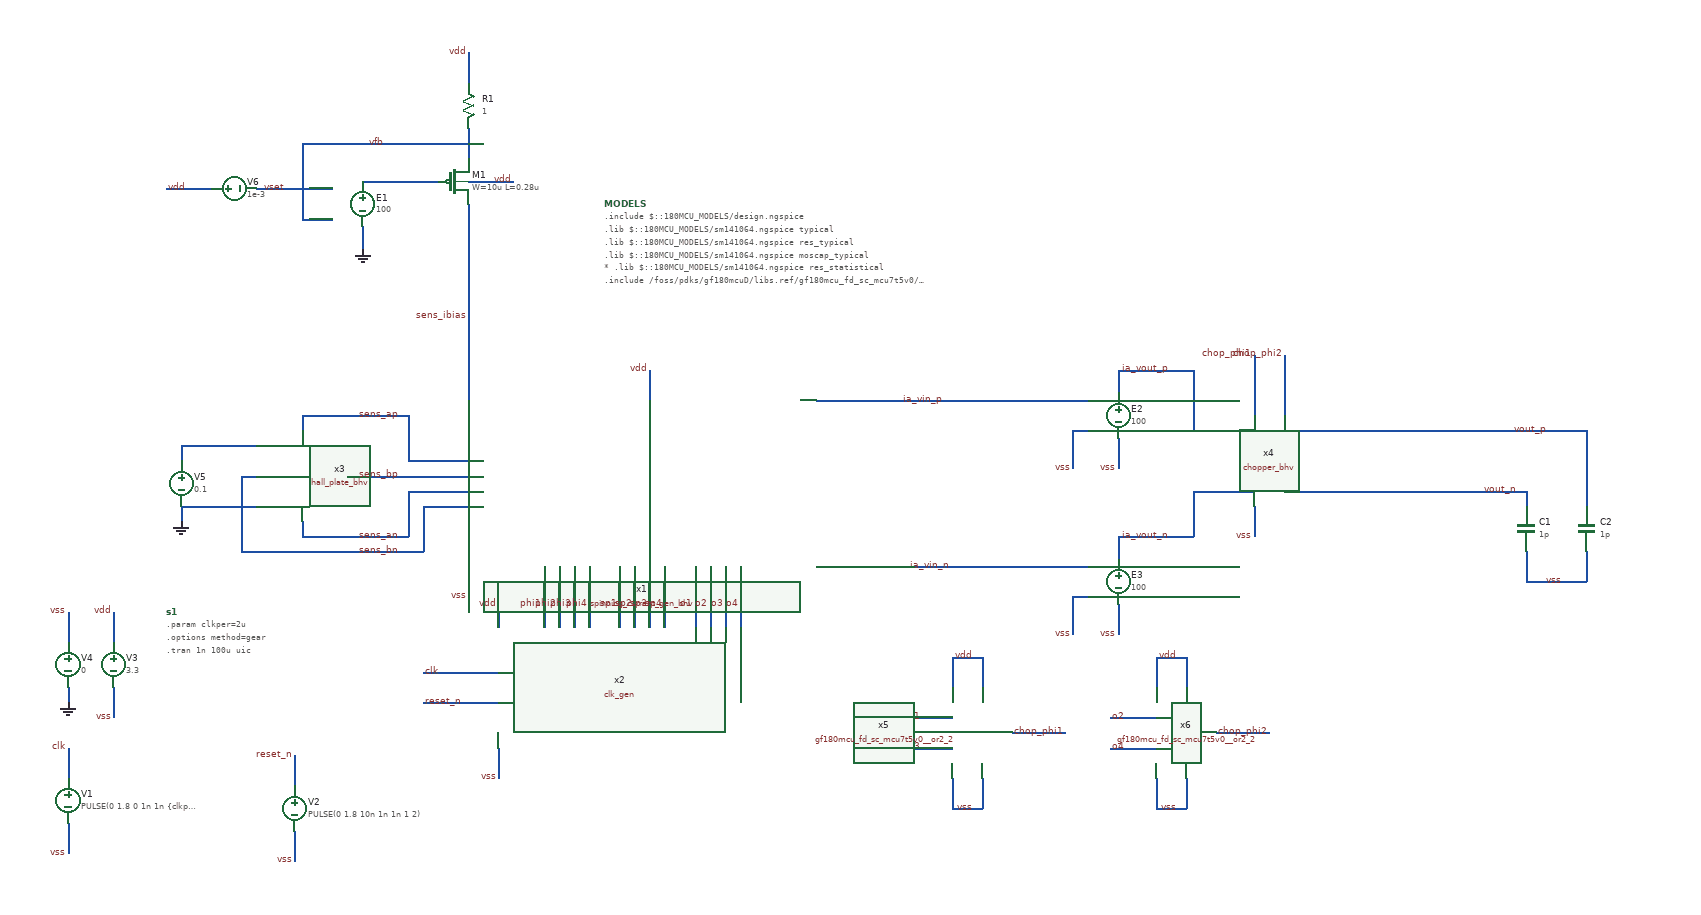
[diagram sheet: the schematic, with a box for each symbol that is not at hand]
v {xschem version=3.4.8RC file_version=1.3}
G {}
K {}
V {}
S {}
F {}
E {}
N 1020 -480 1020 -400 {lab=phi1}
N 1040 -480 1040 -400 {lab=phi2}
N 1060 -480 1060 -400 {lab=phi3}
N 1080 -480 1080 -400 {lab=phi4}
N 1120 -480 1120 -400 {lab=sp1}
N 1140 -480 1140 -400 {lab=sp2}
N 1160 -480 1160 -400 {lab=sp3}
N 1180 -480 1180 -400 {lab=sp4}
N 1220 -480 1220 -400 {lab=o1}
N 1240 -480 1240 -400 {lab=o2}
N 1260 -480 1260 -400 {lab=o3}
N 1280 -480 1280 -400 {lab=o4}
N 700 -680 700 -660 {lab=sens_ap}
N 710 -680 840 -680 {lab=sens_ap}
N 840 -680 840 -620 {lab=sens_ap}
N 840 -620 920 -620 {lab=sens_ap}
N 770 -600 920 -600 {lab=sens_bp}
N 710 -520 840 -520 {lab=sens_an}
N 840 -580 840 -520 {lab=sens_an}
N 840 -580 920 -580 {lab=sens_an}
N 700 -680 710 -680 {lab=sens_ap}
N 700 -520 710 -520 {lab=sens_an}
N 700 -540 700 -520 {lab=sens_an}
N 880 -560 920 -560 {lab=sens_bn}
N 860 -560 860 -500 {lab=sens_bn}
N 620 -600 620 -500 {lab=sens_bn}
N 620 -600 640 -600 {lab=sens_bn}
N 860 -560 880 -560 {lab=sens_bn}
N 620 -500 860 -500 {lab=sens_bn}
N 920 -480 920 -440 {lab=vss}
N 1160 -740 1160 -700 {lab=vdd}
N 920 -820 920 -700 {lab=sens_ibias}
N 1380 -700 1480 -700 {lab=ia_vin_p}
N 1380 -480 1480 -480 {lab=ia_vin_n}
N 960 -420 960 -400 {lab=vdd}
N 960 -430 960 -420 {lab=vdd}
N 960 -240 960 -200 {lab=vss}
N 760 -600 770 -600 {lab=sens_bp}
N 860 -340 960 -340 {lab=clk}
N 860 -300 960 -300 {lab=reset_n}
N 390 -320 390 -300 {lab=0}
N 390 -420 390 -390 {lab=vss}
N 390 -390 390 -380 {lab=vss}
N 450 -320 450 -300 {lab=vss}
N 450 -300 450 -280 {lab=vss}
N 450 -420 450 -380 {lab=vdd}
N 390 -140 390 -120 {lab=vss}
N 390 -120 390 -100 {lab=vss}
N 390 -240 390 -200 {lab=clk}
N 690 -130 690 -110 {lab=vss}
N 690 -110 690 -90 {lab=vss}
N 690 -230 690 -190 {lab=reset_n}
N 550 -640 640 -640 {lab=#net1}
N 540 -560 640 -560 {lab=0}
N 540 -640 550 -640 {lab=#net1}
N 540 -640 540 -620 {lab=#net1}
N 540 -560 540 -540 {lab=0}
N 920 -920 920 -820 {lab=sens_ibias}
N 920 -960 920 -920 {lab=sens_ibias}
N 920 -990 980 -990 {lab=vdd}
N 920 -1060 920 -1020 {lab=vfb}
N 780 -990 880 -990 {lab=#net2}
N 700 -1040 920 -1040 {lab=vfb}
N 640 -980 680 -980 {lab=vset}
N 920 -1160 920 -1120 {lab=vdd}
N 520 -980 580 -980 {lab=vdd}
N 780 -930 780 -900 {lab=0}
N 700 -940 740 -940 {lab=vfb}
N 700 -1040 700 -940 {lab=vfb}
N 680 -980 740 -980 {lab=vset}
N 1780 -650 1780 -610 {lab=vss}
N 1780 -430 1780 -390 {lab=vss}
N 1480 -480 1740 -480 {lab=ia_vin_n}
N 1480 -700 1740 -700 {lab=ia_vin_p}
N 1720 -650 1720 -610 {lab=vss}
N 1720 -430 1720 -390 {lab=vss}
N 1720 -660 1720 -650 {lab=vss}
N 1720 -660 1740 -660 {lab=vss}
N 1720 -440 1720 -430 {lab=vss}
N 1720 -440 1740 -440 {lab=vss}
N 1780 -740 1780 -710 {lab=ia_vout_p}
N 1780 -740 1880 -740 {lab=ia_vout_p}
N 1780 -520 1780 -490 {lab=ia_vout_n}
N 1780 -520 1880 -520 {lab=ia_vout_n}
N 1880 -740 1880 -660 {lab=ia_vout_p}
N 1880 -660 1960 -660 {lab=ia_vout_p}
N 1880 -580 1880 -520 {lab=ia_vout_n}
N 1880 -580 1960 -580 {lab=ia_vout_n}
N 2000 -660 2100 -660 {lab=vout_p}
N 2000 -580 2100 -580 {lab=vout_n}
N 2320 -580 2320 -560 {lab=vout_n}
N 2320 -660 2400 -660 {lab=vout_p}
N 2400 -660 2400 -560 {lab=vout_p}
N 2320 -500 2320 -460 {lab=vss}
N 2320 -460 2400 -460 {lab=vss}
N 2400 -500 2400 -460 {lab=vss}
N 1500 -280 1560 -280 {lab=o1}
N 1500 -240 1560 -240 {lab=o3}
N 1560 -360 1560 -320 {lab=vdd}
N 1600 -360 1600 -320 {lab=vdd}
N 1560 -360 1600 -360 {lab=vdd}
N 1560 -200 1560 -160 {lab=vss}
N 1560 -160 1600 -160 {lab=vss}
N 1600 -200 1600 -160 {lab=vss}
N 1960 -560 1960 -520 {lab=vss}
N 1680 -260 1710 -260 {lab=chop_phi1}
N 1770 -280 1830 -280 {lab=o2}
N 1770 -240 1830 -240 {lab=o4}
N 1830 -360 1830 -320 {lab=vdd}
N 1870 -360 1870 -320 {lab=vdd}
N 1830 -360 1870 -360 {lab=vdd}
N 1830 -200 1830 -160 {lab=vss}
N 1830 -160 1870 -160 {lab=vss}
N 1870 -200 1870 -160 {lab=vss}
N 1950 -260 1980 -260 {lab=chop_phi2}
N 1960 -750 1960 -680 {lab=chop_phi1}
N 2000 -750 2000 -680 {lab=chop_phi2}
N 1960 -760 1960 -750 {lab=chop_phi1}
N 2000 -760 2000 -750 {lab=chop_phi2}
N 1640 -260 1680 -260 {lab=chop_phi1}
N 1910 -260 1950 -260 {lab=chop_phi2}
N 2100 -580 2140 -580 {lab=vout_n}
N 2100 -660 2140 -660 {lab=vout_p}
N 2200 -660 2320 -660 {lab=vout_p}
N 2200 -580 2320 -580 {lab=vout_n}
N 2140 -660 2200 -660 {lab=vout_p}
N 2140 -580 2200 -580 {lab=vout_n}
C {title.sym} 160 -40 0 0 {name=l1 author="alang"}
C {spinning_current_gen_bhv/spinning_current_gen_bhv.sym} 920 -480 0 0 {name=x1}
C {hall_plate_bhv/hall_plate_bhv.sym} 640 -540 0 0 {name=x3}
C {lab_wire.sym} 830 -680 0 0 {name=p17 sig_type=std_logic lab=sens_ap}
C {lab_wire.sym} 830 -600 0 0 {name=p18 sig_type=std_logic lab=sens_bp}
C {lab_wire.sym} 830 -520 0 0 {name=p19 sig_type=std_logic lab=sens_an}
C {lab_wire.sym} 830 -500 0 0 {name=p20 sig_type=std_logic lab=sens_bn}
C {lab_wire.sym} 920 -440 1 0 {name=p21 sig_type=std_logic lab=vss}
C {lab_wire.sym} 1160 -740 1 1 {name=p22 sig_type=std_logic lab=vdd}
C {lab_wire.sym} 960 -430 3 0 {name=p23 sig_type=std_logic lab=vdd}
C {lab_wire.sym} 960 -200 3 1 {name=p24 sig_type=std_logic lab=vss}
C {lab_wire.sym} 1020 -430 3 1 {name=p25 sig_type=std_logic lab=phi1}
C {lab_wire.sym} 1040 -430 3 1 {name=p26 sig_type=std_logic lab=phi2}
C {lab_wire.sym} 1060 -430 3 1 {name=p27 sig_type=std_logic lab=phi3}
C {lab_wire.sym} 1080 -430 3 1 {name=p28 sig_type=std_logic lab=phi4}
C {lab_wire.sym} 1120 -430 3 1 {name=p29 sig_type=std_logic lab=sp1}
C {lab_wire.sym} 1140 -430 3 1 {name=p30 sig_type=std_logic lab=sp2}
C {lab_wire.sym} 1160 -430 3 1 {name=p31 sig_type=std_logic lab=sp3}
C {lab_wire.sym} 1180 -430 3 1 {name=p32 sig_type=std_logic lab=sp4}
C {lab_wire.sym} 1220 -430 3 1 {name=p33 sig_type=std_logic lab=o1}
C {lab_wire.sym} 1240 -430 3 1 {name=p34 sig_type=std_logic lab=o2}
C {lab_wire.sym} 1260 -430 3 1 {name=p35 sig_type=std_logic lab=o3}
C {lab_wire.sym} 1280 -430 3 1 {name=p36 sig_type=std_logic lab=o4}
C {lab_wire.sym} 860 -300 0 1 {name=p47 sig_type=std_logic lab=reset_n}
C {lab_wire.sym} 860 -340 0 1 {name=p15 sig_type=std_logic lab=clk}
C {clk_gen/clk_gen.sym} 960 -240 0 0 {name=x2}
C {vsource.sym} 390 -170 0 0 {name=V1 value="PULSE(0 1.8 0 1n 1n \{clkper/2\} \{clkper\})" savecurrent=false}
C {vsource.sym} 450 -350 0 0 {name=V3 value=3.3 savecurrent=false}
C {vsource.sym} 390 -350 0 0 {name=V4 value=0 savecurrent=false}
C {gnd.sym} 390 -300 0 0 {name=l2 lab=0}
C {lab_wire.sym} 390 -420 3 0 {name=p1 sig_type=std_logic lab=vss}
C {lab_wire.sym} 450 -280 3 1 {name=p2 sig_type=std_logic lab=vss}
C {lab_wire.sym} 450 -420 3 0 {name=p3 sig_type=std_logic lab=vdd}
C {lab_wire.sym} 390 -100 3 1 {name=p4 sig_type=std_logic lab=vss}
C {lab_wire.sym} 390 -240 1 1 {name=p5 sig_type=std_logic lab=clk}
C {vsource.sym} 690 -160 0 0 {name=V2 value="PULSE(0 1.8 10n 1n 1n 1 2)" savecurrent=false}
C {lab_wire.sym} 690 -90 3 1 {name=p6 sig_type=std_logic lab=vss}
C {lab_wire.sym} 690 -230 1 1 {name=p7 sig_type=std_logic lab=reset_n}
C {code_shown.sym} 520 -420 0 0 {name=s1 only_toplevel=false value=".param clkper=2u
.options method=gear
.tran 1n 100u uic"}
C {devices/code_shown.sym} 1100 -960 0 0 {name=MODELS only_toplevel=true
format="tcleval( @value )"
value="
.include $::180MCU_MODELS/design.ngspice
.lib $::180MCU_MODELS/sm141064.ngspice typical
.lib $::180MCU_MODELS/sm141064.ngspice res_typical
.lib $::180MCU_MODELS/sm141064.ngspice moscap_typical
* .lib $::180MCU_MODELS/sm141064.ngspice res_statistical
.include /foss/pdks/gf180mcuD/libs.ref/gf180mcu_fd_sc_mcu7t5v0/spice/gf180mcu_fd_sc_mcu7t5v0.spice
"}
C {vsource.sym} 540 -590 0 0 {name=V5 value=0.1 savecurrent=false}
C {gnd.sym} 540 -540 0 0 {name=l3 lab=0}
C {symbols/pfet_03v3.sym} 900 -990 0 0 {name=M1
L=0.28u
W=10u
nf=1
m=1
ad="'int((nf+1)/2) * W/nf * 0.18u'"
pd="'2*int((nf+1)/2) * (W/nf + 0.18u)'"
as="'int((nf+2)/2) * W/nf * 0.18u'"
ps="'2*int((nf+2)/2) * (W/nf + 0.18u)'"
nrd="'0.18u / W'" nrs="'0.18u / W'"
sa=0 sb=0 sd=0
model=pfet_03v3
spiceprefix=X
}
C {lab_wire.sym} 980 -990 0 0 {name=p8 sig_type=std_logic lab=vdd}
C {res.sym} 920 -1090 0 0 {name=R1
value=1
footprint=1206
device=resistor
m=1}
C {vcvs.sym} 780 -960 0 0 {name=E1 value=100}
C {lab_wire.sym} 920 -1160 1 1 {name=p9 sig_type=std_logic lab=vdd}
C {vsource.sym} 610 -980 3 0 {name=V6 value=1e-3 savecurrent=false}
C {lab_wire.sym} 520 -980 0 1 {name=p10 sig_type=std_logic lab=vdd}
C {gnd.sym} 780 -900 0 0 {name=l4 lab=0}
C {lab_wire.sym} 810 -1040 0 0 {name=p11 sig_type=std_logic lab=vfb}
C {lab_wire.sym} 680 -980 0 0 {name=p12 sig_type=std_logic lab=vset}
C {lab_wire.sym} 920 -810 1 1 {name=p13 sig_type=std_logic lab=sens_ibias}
C {vcvs.sym} 1780 -680 0 0 {name=E2 value=100}
C {lab_wire.sym} 1780 -610 3 1 {name=p14 sig_type=std_logic lab=vss}
C {vcvs.sym} 1780 -460 0 0 {name=E3 value=100}
C {lab_wire.sym} 1780 -390 3 1 {name=p16 sig_type=std_logic lab=vss}
C {lab_wire.sym} 1560 -480 0 0 {name=p37 sig_type=std_logic lab=ia_vin_n}
C {lab_wire.sym} 1550 -700 0 0 {name=p38 sig_type=std_logic lab=ia_vin_p}
C {lab_wire.sym} 1720 -610 3 1 {name=p39 sig_type=std_logic lab=vss}
C {lab_wire.sym} 1720 -390 3 1 {name=p40 sig_type=std_logic lab=vss}
C {chopper_bhv/chopper_bhv.sym} 1960 -560 0 0 {name=x4}
C {capa.sym} 2320 -530 0 0 {name=C1
m=1
value=1p
footprint=1206
device="ceramic capacitor"}
C {capa.sym} 2400 -530 0 0 {name=C2
m=1
value=1p
footprint=1206
device="ceramic capacitor"}
C {lab_wire.sym} 2370 -460 0 0 {name=p41 sig_type=std_logic lab=vss}
C {lab_wire.sym} 1850 -740 0 0 {name=p42 sig_type=std_logic lab=ia_vout_p}
C {lab_wire.sym} 1850 -520 0 0 {name=p43 sig_type=std_logic lab=ia_vout_n}
C {lab_wire.sym} 2350 -660 0 0 {name=p44 sig_type=std_logic lab=vout_p
}
C {lab_wire.sym} 2310 -580 0 0 {name=p45 sig_type=std_logic lab=vout_n}
C {lab_wire.sym} 1500 -280 0 1 {name=p46 sig_type=std_logic lab=o1}
C {lab_wire.sym} 1500 -240 0 1 {name=p48 sig_type=std_logic lab=o3}
C {lab_wire.sym} 1590 -360 0 0 {name=p49 sig_type=std_logic lab=vdd}
C {lab_wire.sym} 1590 -160 2 1 {name=p50 sig_type=std_logic lab=vss}
C {lab_wire.sym} 1960 -520 3 1 {name=p51 sig_type=std_logic lab=vss}
C {lab_wire.sym} 1710 -260 0 0 {name=p52 sig_type=std_logic lab=chop_phi1}
C {lab_wire.sym} 1770 -280 0 1 {name=p53 sig_type=std_logic lab=o2}
C {lab_wire.sym} 1770 -240 0 1 {name=p54 sig_type=std_logic lab=o4}
C {lab_wire.sym} 1860 -360 0 0 {name=p55 sig_type=std_logic lab=vdd}
C {lab_wire.sym} 1860 -160 2 1 {name=p56 sig_type=std_logic lab=vss}
C {lab_wire.sym} 1980 -260 0 0 {name=p57 sig_type=std_logic lab=chop_phi2}
C {lab_wire.sym} 1960 -760 3 0 {name=p58 sig_type=std_logic lab=chop_phi1}
C {lab_wire.sym} 2000 -760 3 0 {name=p59 sig_type=std_logic lab=chop_phi2}
C {mcu7t5v0/gf180mcu_fd_sc_mcu7t5v0__or2_2.sym} 1560 -200 0 0 {name=x5}
C {mcu7t5v0/gf180mcu_fd_sc_mcu7t5v0__or2_2.sym} 1830 -200 0 0 {name=x6}
